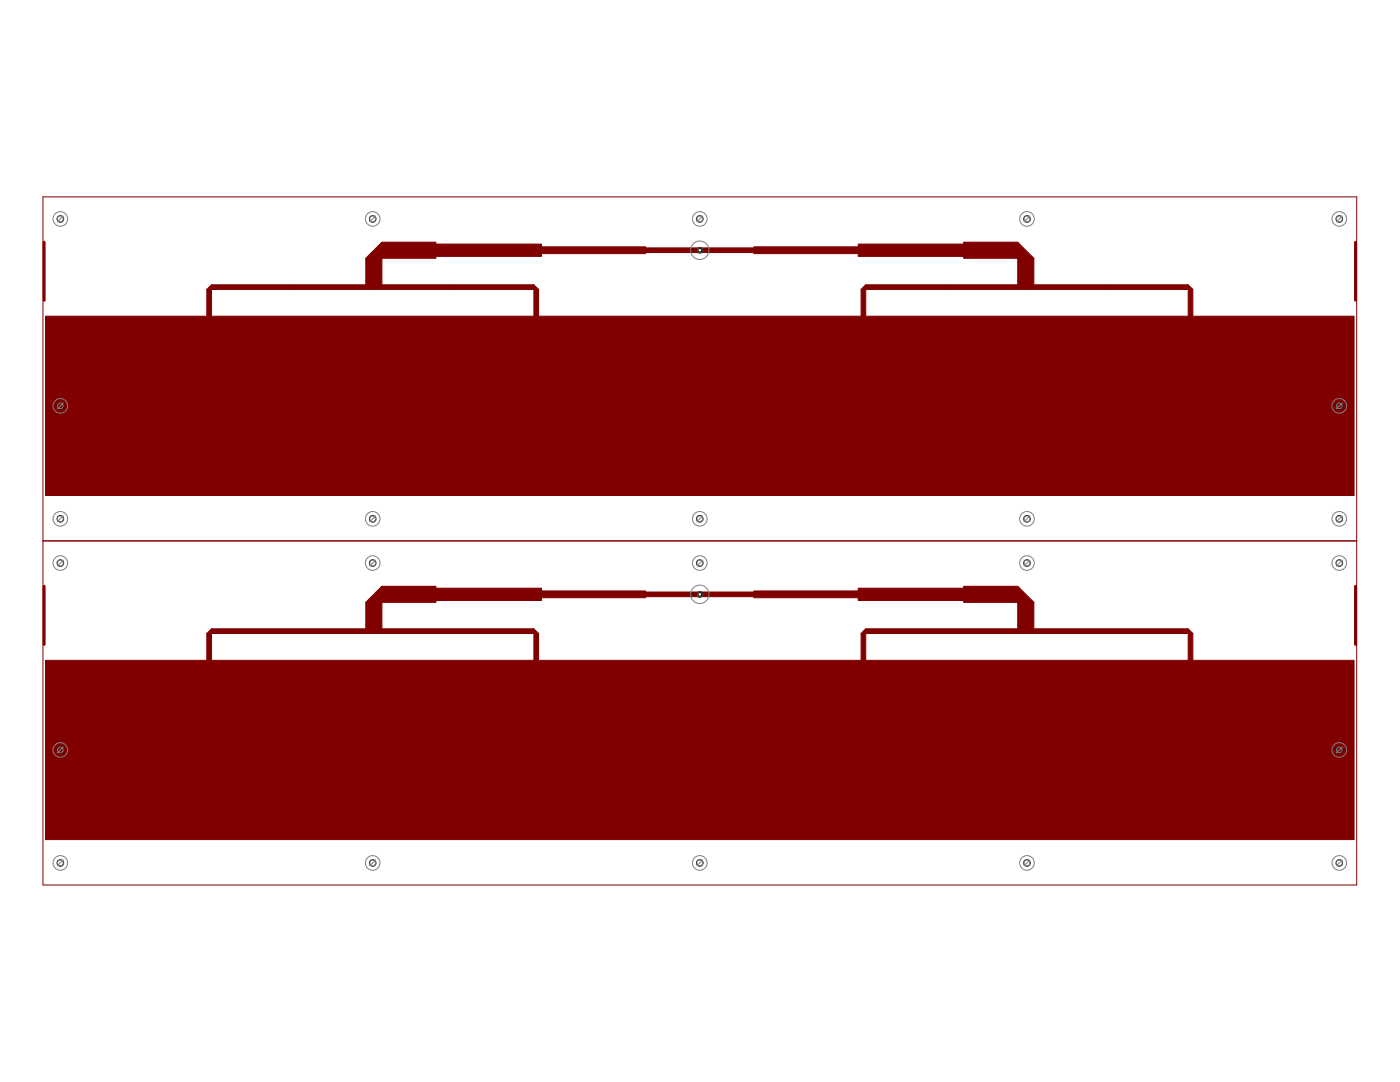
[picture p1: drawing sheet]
<svg xmlns="http://www.w3.org/2000/svg" width="279mm" height="216mm" viewBox="0 0 279 216" stroke-linecap="round" stroke-linejoin="round" font-family="sans-serif">
<circle cx="139.7" cy="118.6" r=".55" fill="#008000" stroke="#008000" stroke-width=".2"/>
<circle cx="139.7" cy="118.6" r=".36" fill="#fff" stroke="#000" stroke-width=".2"/>
<circle cx="139.7" cy="49.9" r=".55" fill="#008000" stroke="#008000" stroke-width=".2"/>
<circle cx="139.7" cy="49.9" r=".36" fill="#fff" stroke="#000" stroke-width=".2"/>
<g fill="#800000" stroke="#800000" stroke-width=".2">
<path d="M128.9 118.1h10.8v1h-10.8z"/>
<path d="M139.7 118.1h10.8v1h-10.8z"/>
<path d="M108 117.9h20.9v1.4h-20.9z"/>
<path d="M150.5 117.9h20.8v1.4h-20.8z"/>
<path d="M87 117.4h21.1v2.4h-21.1z"/>
<path d="M171.3 117.4h21v2.4h-21z"/>
<path d="M76.2 117h10.8v3.2h-10.8z"/>
<path d="M192.3 117h10.8v3.2h-10.8z"/>
<path d="M73 120.2l3.2-3.2 1.6 1.6-3.2 3.2z"/>
<path d="M203.1 117l3.2 3.2-1.6 1.6-3.2-3.2z"/>
<path d="M73 120.2h3.2v5.7h-3.2z"/>
<path d="M203.1 120.2h3.2v5.7h-3.2z"/>
<path d="M58.3 125.5h16.1v.9h-16.1z"/>
<path d="M74.4 125.5h16.1v.9h-16.1z"/>
<path d="M42.2 125.5h16.1v.9h-16.1z"/>
<path d="M90.5 125.5h16.1v.9h-16.1z"/>
<path d="M41.3 126.4l.9-.9 .5 .4-1 1z"/>
<path d="M236.7 125.9l.4-.4 1 .9-.5 .5z"/>
<path d="M41.3 126.4h.9v5.3h-.9z"/>
<path d="M106.6 126.4h.9v5.3h-.9z"/>
<path d="M188.9 125.5h16.1v.9h-16.1z"/>
<path d="M205 125.5h16v.9h-16z"/>
<path d="M172.8 125.5h16v.9h-16z"/>
<path d="M221 125.5h16.1v.9h-16.1z"/>
<path d="M172.8 125.5l.4 .4-.9 1-.5-.5z"/>
<path d="M106.6 125.5l.9 .9-.5 .5-.9-1z"/>
<path d="M171.8 126.4h1v5.3h-1z"/>
<path d="M237.1 126.4h1v5.3h-1z"/>
<path d="M9.1 131.8h261.1v35.7h-261.1z"/>
<path d="M128.9 49.5h10.8v.9h-10.8z"/>
<path d="M139.7 49.5h10.8v.9h-10.8z"/>
<path d="M108 49.3h20.9v1.3h-20.9z"/>
<path d="M150.5 49.3h20.8v1.3h-20.8z"/>
<path d="M87 48.7h21.1v2.5h-21.1z"/>
<path d="M171.3 48.7h21v2.5h-21z"/>
<path d="M76.2 48.3h10.8v3.2h-10.8z"/>
<path d="M192.3 48.3h10.8v3.2h-10.8z"/>
<path d="M73 51.5l3.2-3.2 1.6 1.6-3.2 3.2z"/>
<path d="M203.1 48.3l3.2 3.2-1.6 1.6-3.2-3.2z"/>
<path d="M73 51.5h3.2v5.8h-3.2z"/>
<path d="M203.1 51.5h3.2v5.8h-3.2z"/>
<path d="M58.3 56.8h16.1v1h-16.1z"/>
<path d="M74.4 56.8h16.1v1h-16.1z"/>
<path d="M42.2 56.8h16.1v1h-16.1z"/>
<path d="M90.5 56.8h16.1v1h-16.1z"/>
<path d="M41.3 57.7l.9-.9 .5 .5-1 .9z"/>
<path d="M236.7 57.3l.4-.5 1 .9-.5 .5z"/>
<path d="M41.3 57.8h.9v5.3h-.9z"/>
<path d="M106.6 57.8h.9v5.3h-.9z"/>
<path d="M188.9 56.8h16.1v1h-16.1z"/>
<path d="M205 56.8h16v1h-16z"/>
<path d="M172.8 56.8h16v1h-16z"/>
<path d="M221 56.8h16.1v1h-16.1z"/>
<path d="M171.8 57.7l1-.9 .4 .5-.9 .9z"/>
<path d="M106.6 56.8l.9 .9-.5 .5-.9-.9z"/>
<path d="M171.8 57.8h1v5.3h-1z"/>
<path d="M237.1 57.8h1v5.3h-1z"/>
<path d="M9.1 63.1h261.1v35.8h-261.1z"/>
</g>
<g fill="#800000" stroke="#800000" stroke-width=".59">
<path d="M270.5 117v11.6z"/>
<path d="M8.8 117v11.6z"/>
<path d="M270.5 48.3v11.6z"/>
<path d="M8.8 48.3v11.6z"/>
</g>
<g fill="#800000" stroke="#800000" stroke-width=".2">
<path d="M8.6 107.9h262.2z"/>
<path d="M8.6 107.9v68.7z"/>
<path d="M8.6 176.6h262.2z"/>
<path d="M270.8 107.9v68.7z"/>
<path d="M8.6 39.3h262.2z"/>
<path d="M8.6 39.3v68.6z"/>
<path d="M270.8 39.3v68.6z"/>
</g>
<circle cx="139.7" cy="118.6" r=".55" fill="#008000" stroke="#008000" stroke-width=".2"/>
<circle cx="139.7" cy="118.6" r=".36" fill="#fff" stroke="#000" stroke-width=".2"/>
<circle cx="139.7" cy="49.9" r=".55" fill="#008000" stroke="#008000" stroke-width=".2"/>
<circle cx="139.7" cy="49.9" r=".36" fill="#fff" stroke="#000" stroke-width=".2"/>
<g fill="none" stroke="#808080" stroke-width=".2">
<circle cx="12" cy="43.7" r="1.46"/>
<circle cx="12" cy="43.7" r=".57"/>
<circle cx="74.4" cy="43.7" r="1.46"/>
<circle cx="74.4" cy="43.7" r=".57"/>
<circle cx="139.7" cy="49.9" r="1.84"/>
<circle cx="139.7" cy="43.7" r="1.46"/>
<circle cx="139.7" cy="43.7" r=".57"/>
<circle cx="205" cy="43.7" r="1.46"/>
<circle cx="205" cy="43.7" r=".57"/>
<circle cx="267.3" cy="43.7" r="1.46"/>
<circle cx="267.3" cy="43.7" r=".57"/>
<circle cx="12" cy="81" r="1.46"/>
<circle cx="12" cy="81" r=".57"/>
<circle cx="267.3" cy="81" r="1.46"/>
<circle cx="267.3" cy="81" r=".57"/>
<circle cx="12" cy="103.5" r="1.46"/>
<circle cx="12" cy="112.4" r="1.46"/>
<circle cx="12" cy="112.4" r=".57"/>
<circle cx="12" cy="103.5" r=".57"/>
<circle cx="74.4" cy="112.4" r="1.46"/>
<circle cx="74.4" cy="103.5" r="1.46"/>
<circle cx="74.4" cy="103.5" r=".57"/>
<circle cx="74.4" cy="112.4" r=".57"/>
<circle cx="139.7" cy="118.6" r="1.84"/>
<circle cx="139.7" cy="103.5" r="1.46"/>
<circle cx="139.7" cy="112.4" r="1.46"/>
<circle cx="139.7" cy="103.5" r=".57"/>
<circle cx="139.7" cy="112.4" r=".57"/>
<circle cx="205" cy="103.5" r="1.46"/>
<circle cx="205" cy="112.4" r="1.46"/>
<circle cx="205" cy="112.4" r=".57"/>
<circle cx="205" cy="103.5" r=".57"/>
<circle cx="267.3" cy="103.5" r="1.46"/>
<circle cx="267.3" cy="112.4" r="1.46"/>
<circle cx="267.3" cy="103.5" r=".57"/>
<circle cx="267.3" cy="112.4" r=".57"/>
<circle cx="12" cy="149.6" r="1.46"/>
<circle cx="12" cy="149.6" r=".57"/>
<circle cx="267.3" cy="149.6" r="1.46"/>
<circle cx="267.3" cy="149.6" r=".57"/>
<circle cx="12" cy="172.2" r="1.46"/>
<circle cx="12" cy="172.2" r=".57"/>
<circle cx="74.4" cy="172.2" r="1.46"/>
<circle cx="74.4" cy="172.2" r=".57"/>
<circle cx="139.7" cy="172.2" r="1.46"/>
<circle cx="139.7" cy="172.2" r=".57"/>
<circle cx="205" cy="172.2" r="1.46"/>
<circle cx="205" cy="172.2" r=".57"/>
<circle cx="267.3" cy="172.2" r="1.46"/>
<circle cx="267.3" cy="172.2" r=".57"/>
</g>
<g fill="none" stroke="#000" stroke-width=".2">
<circle cx="12" cy="43.7" r=".66"/>
<circle cx="74.4" cy="43.7" r=".66"/>
<circle cx="139.7" cy="43.7" r=".66"/>
<circle cx="205" cy="43.7" r=".66"/>
<circle cx="267.3" cy="43.7" r=".66"/>
<circle cx="12" cy="81" r=".66"/>
<circle cx="267.3" cy="81" r=".66"/>
<circle cx="12" cy="103.5" r=".66"/>
<circle cx="12" cy="112.4" r=".66"/>
<circle cx="74.4" cy="103.5" r=".66"/>
<circle cx="74.4" cy="112.4" r=".66"/>
<circle cx="139.7" cy="112.4" r=".66"/>
<circle cx="139.7" cy="103.5" r=".66"/>
<circle cx="205" cy="103.5" r=".66"/>
<circle cx="205" cy="112.4" r=".66"/>
<circle cx="267.3" cy="112.4" r=".66"/>
<circle cx="267.3" cy="103.5" r=".66"/>
<circle cx="12" cy="149.6" r=".66"/>
<circle cx="267.3" cy="149.6" r=".66"/>
<circle cx="12" cy="172.2" r=".66"/>
<circle cx="74.4" cy="172.2" r=".66"/>
<circle cx="139.7" cy="172.2" r=".66"/>
<circle cx="205" cy="172.2" r=".66"/>
<circle cx="267.3" cy="172.2" r=".66"/>
</g>
<g fill="#808080" stroke="#808080" stroke-width=".2">
<path d="M12.6 111.8l-1.1 1.1z"/>
<path d="M12.6 149.1l-1.1 1.1z"/>
<path d="M11.5 172.8l1.1-1.2z"/>
<path d="M73.8 112.9l1.2-1.1z"/>
<path d="M73.8 172.8l1.2-1.2z"/>
<path d="M140.2 111.8l-1.1 1.1z"/>
<path d="M139.1 172.8l1.1-1.2z"/>
<path d="M204.4 112.9l1.1-1.1z"/>
<path d="M204.4 172.8l1.1-1.2z"/>
<path d="M266.7 112.9l1.2-1.1z"/>
<path d="M266.7 150.2l1.2-1.1z"/>
<path d="M266.7 172.8l1.2-1.2z"/>
<path d="M12.6 43.1l-1.1 1.2z"/>
<path d="M11.5 81.6l1.1-1.2z"/>
<path d="M12.6 102.9l-1.1 1.2z"/>
<path d="M75 43.1l-1.2 1.2z"/>
<path d="M73.8 104.1l1.2-1.2z"/>
<path d="M140.2 43.1l-1.1 1.2z"/>
<path d="M140.2 102.9l-1.1 1.2z"/>
<path d="M204.4 44.3l1.1-1.2z"/>
<path d="M204.4 104.1l1.1-1.2z"/>
<path d="M266.7 44.3l1.2-1.2z"/>
<path d="M266.7 81.6l1.2-1.2z"/>
<path d="M266.7 104.1l1.2-1.2z"/>
</g>
</svg>
